One B-rep face of a CAD part: STEP entity #155.
In plain terms, the planar face has unit normal (0, 0, 1).
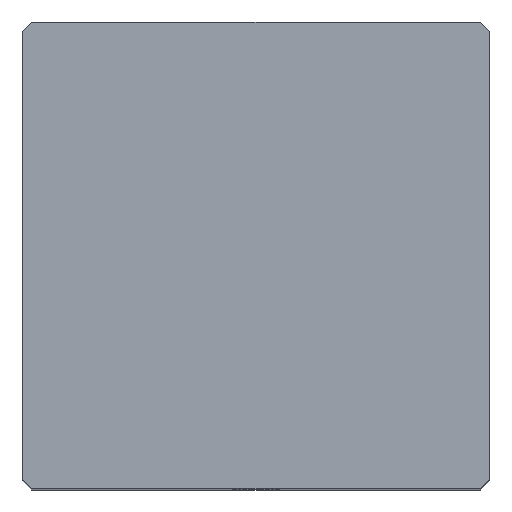
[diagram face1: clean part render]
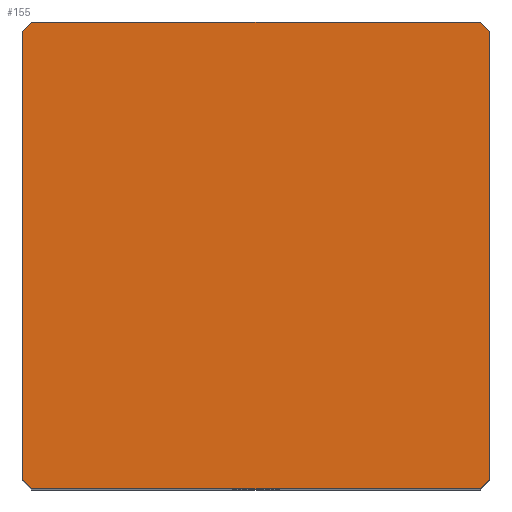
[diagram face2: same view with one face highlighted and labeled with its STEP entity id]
Its self-contained STEP definition (entity closure, numbers rounded to 3 decimals):
#39 = EDGE_CURVE('',#40,#42,#44,.T.);
#40 = VERTEX_POINT('',#41);
#41 = CARTESIAN_POINT('',(-10.,-9.6,27.75));
#42 = VERTEX_POINT('',#43);
#43 = CARTESIAN_POINT('',(-10.,9.6,27.75));
#44 = SURFACE_CURVE('',#45,(#49,#61),.PCURVE_S1.);
#45 = LINE('',#46,#47);
#46 = CARTESIAN_POINT('',(-10.,-10.,27.75));
#47 = VECTOR('',#48,1.);
#48 = DIRECTION('',(-0.,1.,0.));
#49 = PCURVE('',#50,#55);
#50 = PLANE('',#51);
#51 = AXIS2_PLACEMENT_3D('',#52,#53,#54);
#52 = CARTESIAN_POINT('',(-10.,-10.,0.));
#53 = DIRECTION('',(1.,0.,-0.));
#54 = DIRECTION('',(0.,0.,1.));
#55 = DEFINITIONAL_REPRESENTATION('',(#56),#60);
#56 = LINE('',#57,#58);
#57 = CARTESIAN_POINT('',(27.75,0.));
#58 = VECTOR('',#59,1.);
#59 = DIRECTION('',(0.,-1.));
#60 = ( GEOMETRIC_REPRESENTATION_CONTEXT(2) 
PARAMETRIC_REPRESENTATION_CONTEXT() REPRESENTATION_CONTEXT('2D SPACE',''
  ) );
#61 = PCURVE('',#62,#67);
#62 = PLANE('',#63);
#63 = AXIS2_PLACEMENT_3D('',#64,#65,#66);
#64 = CARTESIAN_POINT('',(-10.,-10.,27.75));
#65 = DIRECTION('',(0.,0.,1.));
#66 = DIRECTION('',(1.,0.,-0.));
#67 = DEFINITIONAL_REPRESENTATION('',(#68),#72);
#68 = LINE('',#69,#70);
#69 = CARTESIAN_POINT('',(0.,0.));
#70 = VECTOR('',#71,1.);
#71 = DIRECTION('',(0.,1.));
#72 = ( GEOMETRIC_REPRESENTATION_CONTEXT(2) 
PARAMETRIC_REPRESENTATION_CONTEXT() REPRESENTATION_CONTEXT('2D SPACE',''
  ) );
#90 = PLANE('',#91);
#91 = AXIS2_PLACEMENT_3D('',#92,#93,#94);
#92 = CARTESIAN_POINT('',(-9.8,-9.8,0.));
#93 = DIRECTION('',(-0.707,-0.707,0.));
#94 = DIRECTION('',(-0.,-0.,-1.));
#144 = PLANE('',#145);
#145 = AXIS2_PLACEMENT_3D('',#146,#147,#148);
#146 = CARTESIAN_POINT('',(-9.8,9.8,0.));
#147 = DIRECTION('',(0.707,-0.707,0.));
#148 = DIRECTION('',(-0.,-0.,-1.));
#155 = ADVANCED_FACE('',(#156),#62,.T.);
#156 = FACE_BOUND('',#157,.T.);
#157 = EDGE_LOOP('',(#158,#159,#182,#210,#238,#266,#294,#322));
#158 = ORIENTED_EDGE('',*,*,#39,.F.);
#159 = ORIENTED_EDGE('',*,*,#160,.T.);
#160 = EDGE_CURVE('',#40,#161,#163,.T.);
#161 = VERTEX_POINT('',#162);
#162 = CARTESIAN_POINT('',(-9.6,-10.,27.75));
#163 = SURFACE_CURVE('',#164,(#168,#175),.PCURVE_S1.);
#164 = LINE('',#165,#166);
#165 = CARTESIAN_POINT('',(-9.8,-9.8,27.75));
#166 = VECTOR('',#167,1.);
#167 = DIRECTION('',(0.707,-0.707,0.));
#168 = PCURVE('',#62,#169);
#169 = DEFINITIONAL_REPRESENTATION('',(#170),#174);
#170 = LINE('',#171,#172);
#171 = CARTESIAN_POINT('',(0.2,0.2));
#172 = VECTOR('',#173,1.);
#173 = DIRECTION('',(0.707,-0.707));
#174 = ( GEOMETRIC_REPRESENTATION_CONTEXT(2) 
PARAMETRIC_REPRESENTATION_CONTEXT() REPRESENTATION_CONTEXT('2D SPACE',''
  ) );
#175 = PCURVE('',#90,#176);
#176 = DEFINITIONAL_REPRESENTATION('',(#177),#181);
#177 = LINE('',#178,#179);
#178 = CARTESIAN_POINT('',(-27.75,0.));
#179 = VECTOR('',#180,1.);
#180 = DIRECTION('',(-0.,1.));
#181 = ( GEOMETRIC_REPRESENTATION_CONTEXT(2) 
PARAMETRIC_REPRESENTATION_CONTEXT() REPRESENTATION_CONTEXT('2D SPACE',''
  ) );
#182 = ORIENTED_EDGE('',*,*,#183,.T.);
#183 = EDGE_CURVE('',#161,#184,#186,.T.);
#184 = VERTEX_POINT('',#185);
#185 = CARTESIAN_POINT('',(9.6,-10.,27.75));
#186 = SURFACE_CURVE('',#187,(#191,#198),.PCURVE_S1.);
#187 = LINE('',#188,#189);
#188 = CARTESIAN_POINT('',(-10.,-10.,27.75));
#189 = VECTOR('',#190,1.);
#190 = DIRECTION('',(1.,0.,-0.));
#191 = PCURVE('',#62,#192);
#192 = DEFINITIONAL_REPRESENTATION('',(#193),#197);
#193 = LINE('',#194,#195);
#194 = CARTESIAN_POINT('',(0.,0.));
#195 = VECTOR('',#196,1.);
#196 = DIRECTION('',(1.,0.));
#197 = ( GEOMETRIC_REPRESENTATION_CONTEXT(2) 
PARAMETRIC_REPRESENTATION_CONTEXT() REPRESENTATION_CONTEXT('2D SPACE',''
  ) );
#198 = PCURVE('',#199,#204);
#199 = PLANE('',#200);
#200 = AXIS2_PLACEMENT_3D('',#201,#202,#203);
#201 = CARTESIAN_POINT('',(-10.,-10.,0.));
#202 = DIRECTION('',(-0.,1.,0.));
#203 = DIRECTION('',(0.,0.,1.));
#204 = DEFINITIONAL_REPRESENTATION('',(#205),#209);
#205 = LINE('',#206,#207);
#206 = CARTESIAN_POINT('',(27.75,0.));
#207 = VECTOR('',#208,1.);
#208 = DIRECTION('',(0.,1.));
#209 = ( GEOMETRIC_REPRESENTATION_CONTEXT(2) 
PARAMETRIC_REPRESENTATION_CONTEXT() REPRESENTATION_CONTEXT('2D SPACE',''
  ) );
#210 = ORIENTED_EDGE('',*,*,#211,.F.);
#211 = EDGE_CURVE('',#212,#184,#214,.T.);
#212 = VERTEX_POINT('',#213);
#213 = CARTESIAN_POINT('',(10.,-9.6,27.75));
#214 = SURFACE_CURVE('',#215,(#219,#226),.PCURVE_S1.);
#215 = LINE('',#216,#217);
#216 = CARTESIAN_POINT('',(4.8,-14.8,27.75));
#217 = VECTOR('',#218,1.);
#218 = DIRECTION('',(-0.707,-0.707,0.));
#219 = PCURVE('',#62,#220);
#220 = DEFINITIONAL_REPRESENTATION('',(#221),#225);
#221 = LINE('',#222,#223);
#222 = CARTESIAN_POINT('',(14.8,-4.8));
#223 = VECTOR('',#224,1.);
#224 = DIRECTION('',(-0.707,-0.707));
#225 = ( GEOMETRIC_REPRESENTATION_CONTEXT(2) 
PARAMETRIC_REPRESENTATION_CONTEXT() REPRESENTATION_CONTEXT('2D SPACE',''
  ) );
#226 = PCURVE('',#227,#232);
#227 = PLANE('',#228);
#228 = AXIS2_PLACEMENT_3D('',#229,#230,#231);
#229 = CARTESIAN_POINT('',(9.8,-9.8,0.));
#230 = DIRECTION('',(-0.707,0.707,0.));
#231 = DIRECTION('',(-0.,-0.,-1.));
#232 = DEFINITIONAL_REPRESENTATION('',(#233),#237);
#233 = LINE('',#234,#235);
#234 = CARTESIAN_POINT('',(-27.75,7.071));
#235 = VECTOR('',#236,1.);
#236 = DIRECTION('',(-0.,1.));
#237 = ( GEOMETRIC_REPRESENTATION_CONTEXT(2) 
PARAMETRIC_REPRESENTATION_CONTEXT() REPRESENTATION_CONTEXT('2D SPACE',''
  ) );
#238 = ORIENTED_EDGE('',*,*,#239,.T.);
#239 = EDGE_CURVE('',#212,#240,#242,.T.);
#240 = VERTEX_POINT('',#241);
#241 = CARTESIAN_POINT('',(10.,9.6,27.75));
#242 = SURFACE_CURVE('',#243,(#247,#254),.PCURVE_S1.);
#243 = LINE('',#244,#245);
#244 = CARTESIAN_POINT('',(10.,-10.,27.75));
#245 = VECTOR('',#246,1.);
#246 = DIRECTION('',(-0.,1.,0.));
#247 = PCURVE('',#62,#248);
#248 = DEFINITIONAL_REPRESENTATION('',(#249),#253);
#249 = LINE('',#250,#251);
#250 = CARTESIAN_POINT('',(20.,0.));
#251 = VECTOR('',#252,1.);
#252 = DIRECTION('',(0.,1.));
#253 = ( GEOMETRIC_REPRESENTATION_CONTEXT(2) 
PARAMETRIC_REPRESENTATION_CONTEXT() REPRESENTATION_CONTEXT('2D SPACE',''
  ) );
#254 = PCURVE('',#255,#260);
#255 = PLANE('',#256);
#256 = AXIS2_PLACEMENT_3D('',#257,#258,#259);
#257 = CARTESIAN_POINT('',(10.,-10.,0.));
#258 = DIRECTION('',(1.,0.,-0.));
#259 = DIRECTION('',(0.,0.,1.));
#260 = DEFINITIONAL_REPRESENTATION('',(#261),#265);
#261 = LINE('',#262,#263);
#262 = CARTESIAN_POINT('',(27.75,0.));
#263 = VECTOR('',#264,1.);
#264 = DIRECTION('',(0.,-1.));
#265 = ( GEOMETRIC_REPRESENTATION_CONTEXT(2) 
PARAMETRIC_REPRESENTATION_CONTEXT() REPRESENTATION_CONTEXT('2D SPACE',''
  ) );
#266 = ORIENTED_EDGE('',*,*,#267,.T.);
#267 = EDGE_CURVE('',#240,#268,#270,.T.);
#268 = VERTEX_POINT('',#269);
#269 = CARTESIAN_POINT('',(9.6,10.,27.75));
#270 = SURFACE_CURVE('',#271,(#275,#282),.PCURVE_S1.);
#271 = LINE('',#272,#273);
#272 = CARTESIAN_POINT('',(9.8,9.8,27.75));
#273 = VECTOR('',#274,1.);
#274 = DIRECTION('',(-0.707,0.707,0.));
#275 = PCURVE('',#62,#276);
#276 = DEFINITIONAL_REPRESENTATION('',(#277),#281);
#277 = LINE('',#278,#279);
#278 = CARTESIAN_POINT('',(19.8,19.8));
#279 = VECTOR('',#280,1.);
#280 = DIRECTION('',(-0.707,0.707));
#281 = ( GEOMETRIC_REPRESENTATION_CONTEXT(2) 
PARAMETRIC_REPRESENTATION_CONTEXT() REPRESENTATION_CONTEXT('2D SPACE',''
  ) );
#282 = PCURVE('',#283,#288);
#283 = PLANE('',#284);
#284 = AXIS2_PLACEMENT_3D('',#285,#286,#287);
#285 = CARTESIAN_POINT('',(9.8,9.8,0.));
#286 = DIRECTION('',(0.707,0.707,0.));
#287 = DIRECTION('',(-0.,0.,-1.));
#288 = DEFINITIONAL_REPRESENTATION('',(#289),#293);
#289 = LINE('',#290,#291);
#290 = CARTESIAN_POINT('',(-27.75,0.));
#291 = VECTOR('',#292,1.);
#292 = DIRECTION('',(-0.,1.));
#293 = ( GEOMETRIC_REPRESENTATION_CONTEXT(2) 
PARAMETRIC_REPRESENTATION_CONTEXT() REPRESENTATION_CONTEXT('2D SPACE',''
  ) );
#294 = ORIENTED_EDGE('',*,*,#295,.F.);
#295 = EDGE_CURVE('',#296,#268,#298,.T.);
#296 = VERTEX_POINT('',#297);
#297 = CARTESIAN_POINT('',(-9.6,10.,27.75));
#298 = SURFACE_CURVE('',#299,(#303,#310),.PCURVE_S1.);
#299 = LINE('',#300,#301);
#300 = CARTESIAN_POINT('',(-10.,10.,27.75));
#301 = VECTOR('',#302,1.);
#302 = DIRECTION('',(1.,0.,-0.));
#303 = PCURVE('',#62,#304);
#304 = DEFINITIONAL_REPRESENTATION('',(#305),#309);
#305 = LINE('',#306,#307);
#306 = CARTESIAN_POINT('',(0.,20.));
#307 = VECTOR('',#308,1.);
#308 = DIRECTION('',(1.,0.));
#309 = ( GEOMETRIC_REPRESENTATION_CONTEXT(2) 
PARAMETRIC_REPRESENTATION_CONTEXT() REPRESENTATION_CONTEXT('2D SPACE',''
  ) );
#310 = PCURVE('',#311,#316);
#311 = PLANE('',#312);
#312 = AXIS2_PLACEMENT_3D('',#313,#314,#315);
#313 = CARTESIAN_POINT('',(-10.,10.,0.));
#314 = DIRECTION('',(-0.,1.,0.));
#315 = DIRECTION('',(0.,0.,1.));
#316 = DEFINITIONAL_REPRESENTATION('',(#317),#321);
#317 = LINE('',#318,#319);
#318 = CARTESIAN_POINT('',(27.75,0.));
#319 = VECTOR('',#320,1.);
#320 = DIRECTION('',(0.,1.));
#321 = ( GEOMETRIC_REPRESENTATION_CONTEXT(2) 
PARAMETRIC_REPRESENTATION_CONTEXT() REPRESENTATION_CONTEXT('2D SPACE',''
  ) );
#322 = ORIENTED_EDGE('',*,*,#323,.F.);
#323 = EDGE_CURVE('',#42,#296,#324,.T.);
#324 = SURFACE_CURVE('',#325,(#329,#336),.PCURVE_S1.);
#325 = LINE('',#326,#327);
#326 = CARTESIAN_POINT('',(-14.8,4.8,27.75));
#327 = VECTOR('',#328,1.);
#328 = DIRECTION('',(0.707,0.707,-0.));
#329 = PCURVE('',#62,#330);
#330 = DEFINITIONAL_REPRESENTATION('',(#331),#335);
#331 = LINE('',#332,#333);
#332 = CARTESIAN_POINT('',(-4.8,14.8));
#333 = VECTOR('',#334,1.);
#334 = DIRECTION('',(0.707,0.707));
#335 = ( GEOMETRIC_REPRESENTATION_CONTEXT(2) 
PARAMETRIC_REPRESENTATION_CONTEXT() REPRESENTATION_CONTEXT('2D SPACE',''
  ) );
#336 = PCURVE('',#144,#337);
#337 = DEFINITIONAL_REPRESENTATION('',(#338),#342);
#338 = LINE('',#339,#340);
#339 = CARTESIAN_POINT('',(-27.75,-7.071));
#340 = VECTOR('',#341,1.);
#341 = DIRECTION('',(-0.,1.));
#342 = ( GEOMETRIC_REPRESENTATION_CONTEXT(2) 
PARAMETRIC_REPRESENTATION_CONTEXT() REPRESENTATION_CONTEXT('2D SPACE',''
  ) );
